VERSION 5.7 ;
BUSBITCHARS "[]" ;
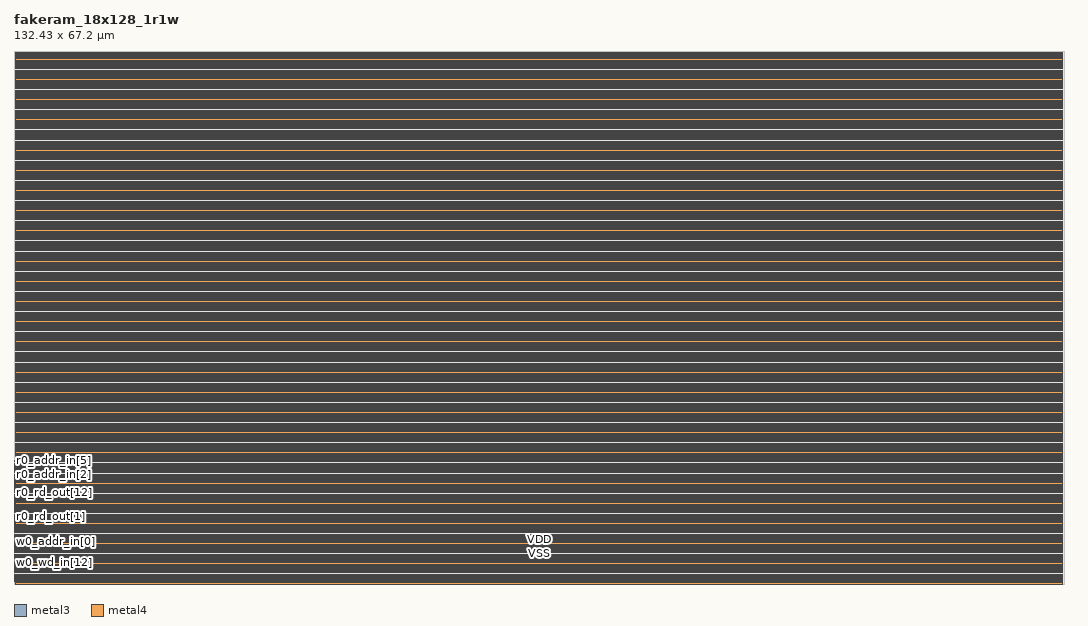
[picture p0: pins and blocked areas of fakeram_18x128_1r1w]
MACRO fakeram_18x128_1r1w
  FOREIGN fakeram_18x128_1r1w 0 0 ;
  SYMMETRY X Y R90 ;
  SIZE 132.430 BY 67.200 ;
  CLASS BLOCK ;
  PIN w0_wd_in[0]
    DIRECTION INPUT ;
    USE SIGNAL ;
    SHAPE ABUTMENT ;
    PORT
      LAYER metal3 ;
      RECT 0.000 0.280 0.140 0.420 ;
    END
  END w0_wd_in[0]
  PIN w0_wd_in[1]
    DIRECTION INPUT ;
    USE SIGNAL ;
    SHAPE ABUTMENT ;
    PORT
      LAYER metal3 ;
      RECT 0.000 0.560 0.140 0.700 ;
    END
  END w0_wd_in[1]
  PIN w0_wd_in[2]
    DIRECTION INPUT ;
    USE SIGNAL ;
    SHAPE ABUTMENT ;
    PORT
      LAYER metal3 ;
      RECT 0.000 0.840 0.140 0.980 ;
    END
  END w0_wd_in[2]
  PIN w0_wd_in[3]
    DIRECTION INPUT ;
    USE SIGNAL ;
    SHAPE ABUTMENT ;
    PORT
      LAYER metal3 ;
      RECT 0.000 1.120 0.140 1.260 ;
    END
  END w0_wd_in[3]
  PIN w0_wd_in[4]
    DIRECTION INPUT ;
    USE SIGNAL ;
    SHAPE ABUTMENT ;
    PORT
      LAYER metal3 ;
      RECT 0.000 1.400 0.140 1.540 ;
    END
  END w0_wd_in[4]
  PIN w0_wd_in[5]
    DIRECTION INPUT ;
    USE SIGNAL ;
    SHAPE ABUTMENT ;
    PORT
      LAYER metal3 ;
      RECT 0.000 1.680 0.140 1.820 ;
    END
  END w0_wd_in[5]
  PIN w0_wd_in[6]
    DIRECTION INPUT ;
    USE SIGNAL ;
    SHAPE ABUTMENT ;
    PORT
      LAYER metal3 ;
      RECT 0.000 1.960 0.140 2.100 ;
    END
  END w0_wd_in[6]
  PIN w0_wd_in[7]
    DIRECTION INPUT ;
    USE SIGNAL ;
    SHAPE ABUTMENT ;
    PORT
      LAYER metal3 ;
      RECT 0.000 2.240 0.140 2.380 ;
    END
  END w0_wd_in[7]
  PIN w0_wd_in[8]
    DIRECTION INPUT ;
    USE SIGNAL ;
    SHAPE ABUTMENT ;
    PORT
      LAYER metal3 ;
      RECT 0.000 2.520 0.140 2.660 ;
    END
  END w0_wd_in[8]
  PIN w0_wd_in[9]
    DIRECTION INPUT ;
    USE SIGNAL ;
    SHAPE ABUTMENT ;
    PORT
      LAYER metal3 ;
      RECT 0.000 2.800 0.140 2.940 ;
    END
  END w0_wd_in[9]
  PIN w0_wd_in[10]
    DIRECTION INPUT ;
    USE SIGNAL ;
    SHAPE ABUTMENT ;
    PORT
      LAYER metal3 ;
      RECT 0.000 3.080 0.140 3.220 ;
    END
  END w0_wd_in[10]
  PIN w0_wd_in[11]
    DIRECTION INPUT ;
    USE SIGNAL ;
    SHAPE ABUTMENT ;
    PORT
      LAYER metal3 ;
      RECT 0.000 3.360 0.140 3.500 ;
    END
  END w0_wd_in[11]
  PIN w0_wd_in[12]
    DIRECTION INPUT ;
    USE SIGNAL ;
    SHAPE ABUTMENT ;
    PORT
      LAYER metal3 ;
      RECT 0.000 3.640 0.140 3.780 ;
    END
  END w0_wd_in[12]
  PIN w0_wd_in[13]
    DIRECTION INPUT ;
    USE SIGNAL ;
    SHAPE ABUTMENT ;
    PORT
      LAYER metal3 ;
      RECT 0.000 3.920 0.140 4.060 ;
    END
  END w0_wd_in[13]
  PIN w0_wd_in[14]
    DIRECTION INPUT ;
    USE SIGNAL ;
    SHAPE ABUTMENT ;
    PORT
      LAYER metal3 ;
      RECT 0.000 4.200 0.140 4.340 ;
    END
  END w0_wd_in[14]
  PIN w0_wd_in[15]
    DIRECTION INPUT ;
    USE SIGNAL ;
    SHAPE ABUTMENT ;
    PORT
      LAYER metal3 ;
      RECT 0.000 4.480 0.140 4.620 ;
    END
  END w0_wd_in[15]
  PIN w0_wd_in[16]
    DIRECTION INPUT ;
    USE SIGNAL ;
    SHAPE ABUTMENT ;
    PORT
      LAYER metal3 ;
      RECT 0.000 4.760 0.140 4.900 ;
    END
  END w0_wd_in[16]
  PIN w0_wd_in[17]
    DIRECTION INPUT ;
    USE SIGNAL ;
    SHAPE ABUTMENT ;
    PORT
      LAYER metal3 ;
      RECT 0.000 5.040 0.140 5.180 ;
    END
  END w0_wd_in[17]
  PIN w0_addr_in[0]
    DIRECTION INPUT ;
    USE SIGNAL ;
    SHAPE ABUTMENT ;
    PORT
      LAYER metal3 ;
      RECT 0.000 5.320 0.140 5.460 ;
    END
  END w0_addr_in[0]
  PIN w0_addr_in[1]
    DIRECTION INPUT ;
    USE SIGNAL ;
    SHAPE ABUTMENT ;
    PORT
      LAYER metal3 ;
      RECT 0.000 5.600 0.140 5.740 ;
    END
  END w0_addr_in[1]
  PIN w0_addr_in[2]
    DIRECTION INPUT ;
    USE SIGNAL ;
    SHAPE ABUTMENT ;
    PORT
      LAYER metal3 ;
      RECT 0.000 5.880 0.140 6.020 ;
    END
  END w0_addr_in[2]
  PIN w0_addr_in[3]
    DIRECTION INPUT ;
    USE SIGNAL ;
    SHAPE ABUTMENT ;
    PORT
      LAYER metal3 ;
      RECT 0.000 6.160 0.140 6.300 ;
    END
  END w0_addr_in[3]
  PIN w0_addr_in[4]
    DIRECTION INPUT ;
    USE SIGNAL ;
    SHAPE ABUTMENT ;
    PORT
      LAYER metal3 ;
      RECT 0.000 6.440 0.140 6.580 ;
    END
  END w0_addr_in[4]
  PIN w0_addr_in[5]
    DIRECTION INPUT ;
    USE SIGNAL ;
    SHAPE ABUTMENT ;
    PORT
      LAYER metal3 ;
      RECT 0.000 6.720 0.140 6.860 ;
    END
  END w0_addr_in[5]
  PIN w0_addr_in[6]
    DIRECTION INPUT ;
    USE SIGNAL ;
    SHAPE ABUTMENT ;
    PORT
      LAYER metal3 ;
      RECT 0.000 7.000 0.140 7.140 ;
    END
  END w0_addr_in[6]
  PIN w0_clk
    DIRECTION INPUT ;
    USE SIGNAL ;
    SHAPE ABUTMENT ;
    PORT
      LAYER metal3 ;
      RECT 0.000 7.280 0.140 7.420 ;
    END
  END w0_clk
  PIN w0_ce_in
    DIRECTION INPUT ;
    USE SIGNAL ;
    SHAPE ABUTMENT ;
    PORT
      LAYER metal3 ;
      RECT 0.000 7.560 0.140 7.700 ;
    END
  END w0_ce_in
  PIN w0_we_in
    DIRECTION INPUT ;
    USE SIGNAL ;
    SHAPE ABUTMENT ;
    PORT
      LAYER metal3 ;
      RECT 0.000 7.840 0.140 7.980 ;
    END
  END w0_we_in
  PIN r0_rd_out[0]
    DIRECTION OUTPUT ;
    USE SIGNAL ;
    SHAPE ABUTMENT ;
    PORT
      LAYER metal3 ;
      RECT 0.000 8.120 0.140 8.260 ;
    END
  END r0_rd_out[0]
  PIN r0_rd_out[1]
    DIRECTION OUTPUT ;
    USE SIGNAL ;
    SHAPE ABUTMENT ;
    PORT
      LAYER metal3 ;
      RECT 0.000 8.400 0.140 8.540 ;
    END
  END r0_rd_out[1]
  PIN r0_rd_out[2]
    DIRECTION OUTPUT ;
    USE SIGNAL ;
    SHAPE ABUTMENT ;
    PORT
      LAYER metal3 ;
      RECT 0.000 8.680 0.140 8.820 ;
    END
  END r0_rd_out[2]
  PIN r0_rd_out[3]
    DIRECTION OUTPUT ;
    USE SIGNAL ;
    SHAPE ABUTMENT ;
    PORT
      LAYER metal3 ;
      RECT 0.000 8.960 0.140 9.100 ;
    END
  END r0_rd_out[3]
  PIN r0_rd_out[4]
    DIRECTION OUTPUT ;
    USE SIGNAL ;
    SHAPE ABUTMENT ;
    PORT
      LAYER metal3 ;
      RECT 0.000 9.240 0.140 9.380 ;
    END
  END r0_rd_out[4]
  PIN r0_rd_out[5]
    DIRECTION OUTPUT ;
    USE SIGNAL ;
    SHAPE ABUTMENT ;
    PORT
      LAYER metal3 ;
      RECT 0.000 9.520 0.140 9.660 ;
    END
  END r0_rd_out[5]
  PIN r0_rd_out[6]
    DIRECTION OUTPUT ;
    USE SIGNAL ;
    SHAPE ABUTMENT ;
    PORT
      LAYER metal3 ;
      RECT 0.000 9.800 0.140 9.940 ;
    END
  END r0_rd_out[6]
  PIN r0_rd_out[7]
    DIRECTION OUTPUT ;
    USE SIGNAL ;
    SHAPE ABUTMENT ;
    PORT
      LAYER metal3 ;
      RECT 0.000 10.080 0.140 10.220 ;
    END
  END r0_rd_out[7]
  PIN r0_rd_out[8]
    DIRECTION OUTPUT ;
    USE SIGNAL ;
    SHAPE ABUTMENT ;
    PORT
      LAYER metal3 ;
      RECT 0.000 10.360 0.140 10.500 ;
    END
  END r0_rd_out[8]
  PIN r0_rd_out[9]
    DIRECTION OUTPUT ;
    USE SIGNAL ;
    SHAPE ABUTMENT ;
    PORT
      LAYER metal3 ;
      RECT 0.000 10.640 0.140 10.780 ;
    END
  END r0_rd_out[9]
  PIN r0_rd_out[10]
    DIRECTION OUTPUT ;
    USE SIGNAL ;
    SHAPE ABUTMENT ;
    PORT
      LAYER metal3 ;
      RECT 0.000 10.920 0.140 11.060 ;
    END
  END r0_rd_out[10]
  PIN r0_rd_out[11]
    DIRECTION OUTPUT ;
    USE SIGNAL ;
    SHAPE ABUTMENT ;
    PORT
      LAYER metal3 ;
      RECT 0.000 11.200 0.140 11.340 ;
    END
  END r0_rd_out[11]
  PIN r0_rd_out[12]
    DIRECTION OUTPUT ;
    USE SIGNAL ;
    SHAPE ABUTMENT ;
    PORT
      LAYER metal3 ;
      RECT 0.000 11.480 0.140 11.620 ;
    END
  END r0_rd_out[12]
  PIN r0_rd_out[13]
    DIRECTION OUTPUT ;
    USE SIGNAL ;
    SHAPE ABUTMENT ;
    PORT
      LAYER metal3 ;
      RECT 0.000 11.760 0.140 11.900 ;
    END
  END r0_rd_out[13]
  PIN r0_rd_out[14]
    DIRECTION OUTPUT ;
    USE SIGNAL ;
    SHAPE ABUTMENT ;
    PORT
      LAYER metal3 ;
      RECT 0.000 12.040 0.140 12.180 ;
    END
  END r0_rd_out[14]
  PIN r0_rd_out[15]
    DIRECTION OUTPUT ;
    USE SIGNAL ;
    SHAPE ABUTMENT ;
    PORT
      LAYER metal3 ;
      RECT 0.000 12.320 0.140 12.460 ;
    END
  END r0_rd_out[15]
  PIN r0_rd_out[16]
    DIRECTION OUTPUT ;
    USE SIGNAL ;
    SHAPE ABUTMENT ;
    PORT
      LAYER metal3 ;
      RECT 0.000 12.600 0.140 12.740 ;
    END
  END r0_rd_out[16]
  PIN r0_rd_out[17]
    DIRECTION OUTPUT ;
    USE SIGNAL ;
    SHAPE ABUTMENT ;
    PORT
      LAYER metal3 ;
      RECT 0.000 12.880 0.140 13.020 ;
    END
  END r0_rd_out[17]
  PIN r0_addr_in[0]
    DIRECTION INPUT ;
    USE SIGNAL ;
    SHAPE ABUTMENT ;
    PORT
      LAYER metal3 ;
      RECT 0.000 13.160 0.140 13.300 ;
    END
  END r0_addr_in[0]
  PIN r0_addr_in[1]
    DIRECTION INPUT ;
    USE SIGNAL ;
    SHAPE ABUTMENT ;
    PORT
      LAYER metal3 ;
      RECT 0.000 13.440 0.140 13.580 ;
    END
  END r0_addr_in[1]
  PIN r0_addr_in[2]
    DIRECTION INPUT ;
    USE SIGNAL ;
    SHAPE ABUTMENT ;
    PORT
      LAYER metal3 ;
      RECT 0.000 13.720 0.140 13.860 ;
    END
  END r0_addr_in[2]
  PIN r0_addr_in[3]
    DIRECTION INPUT ;
    USE SIGNAL ;
    SHAPE ABUTMENT ;
    PORT
      LAYER metal3 ;
      RECT 0.000 14.000 0.140 14.140 ;
    END
  END r0_addr_in[3]
  PIN r0_addr_in[4]
    DIRECTION INPUT ;
    USE SIGNAL ;
    SHAPE ABUTMENT ;
    PORT
      LAYER metal3 ;
      RECT 0.000 14.280 0.140 14.420 ;
    END
  END r0_addr_in[4]
  PIN r0_addr_in[5]
    DIRECTION INPUT ;
    USE SIGNAL ;
    SHAPE ABUTMENT ;
    PORT
      LAYER metal3 ;
      RECT 0.000 14.560 0.140 14.700 ;
    END
  END r0_addr_in[5]
  PIN r0_addr_in[6]
    DIRECTION INPUT ;
    USE SIGNAL ;
    SHAPE ABUTMENT ;
    PORT
      LAYER metal3 ;
      RECT 0.000 14.840 0.140 14.980 ;
    END
  END r0_addr_in[6]
  PIN r0_clk
    DIRECTION INPUT ;
    USE SIGNAL ;
    SHAPE ABUTMENT ;
    PORT
      LAYER metal3 ;
      RECT 0.000 15.120 0.140 15.260 ;
    END
  END r0_clk
  PIN r0_ce_in
    DIRECTION INPUT ;
    USE SIGNAL ;
    SHAPE ABUTMENT ;
    PORT
      LAYER metal3 ;
      RECT 0.000 15.400 0.140 15.540 ;
    END
  END r0_ce_in
  PIN VDD
    DIRECTION INOUT ;
    USE POWER ;
    PORT
      LAYER metal4 ;
      RECT 0.190 0.000 132.240 0.140 ;
      RECT 0.190 0.560 132.240 0.700 ;
      RECT 0.190 1.120 132.240 1.260 ;
      RECT 0.190 1.680 132.240 1.820 ;
      RECT 0.190 2.240 132.240 2.380 ;
      RECT 0.190 2.800 132.240 2.940 ;
      RECT 0.190 3.360 132.240 3.500 ;
      RECT 0.190 3.920 132.240 4.060 ;
      RECT 0.190 4.480 132.240 4.620 ;
      RECT 0.190 5.040 132.240 5.180 ;
      RECT 0.190 5.600 132.240 5.740 ;
      RECT 0.190 6.160 132.240 6.300 ;
      RECT 0.190 6.720 132.240 6.860 ;
      RECT 0.190 7.280 132.240 7.420 ;
      RECT 0.190 7.840 132.240 7.980 ;
      RECT 0.190 8.400 132.240 8.540 ;
      RECT 0.190 8.960 132.240 9.100 ;
      RECT 0.190 9.520 132.240 9.660 ;
      RECT 0.190 10.080 132.240 10.220 ;
      RECT 0.190 10.640 132.240 10.780 ;
      RECT 0.190 11.200 132.240 11.340 ;
      RECT 0.190 11.760 132.240 11.900 ;
      RECT 0.190 12.320 132.240 12.460 ;
      RECT 0.190 12.880 132.240 13.020 ;
      RECT 0.190 13.440 132.240 13.580 ;
      RECT 0.190 14.000 132.240 14.140 ;
      RECT 0.190 14.560 132.240 14.700 ;
      RECT 0.190 15.120 132.240 15.260 ;
      RECT 0.190 15.680 132.240 15.820 ;
      RECT 0.190 16.240 132.240 16.380 ;
      RECT 0.190 16.800 132.240 16.940 ;
      RECT 0.190 17.360 132.240 17.500 ;
      RECT 0.190 17.920 132.240 18.060 ;
      RECT 0.190 18.480 132.240 18.620 ;
      RECT 0.190 19.040 132.240 19.180 ;
      RECT 0.190 19.600 132.240 19.740 ;
      RECT 0.190 20.160 132.240 20.300 ;
      RECT 0.190 20.720 132.240 20.860 ;
      RECT 0.190 21.280 132.240 21.420 ;
      RECT 0.190 21.840 132.240 21.980 ;
      RECT 0.190 22.400 132.240 22.540 ;
      RECT 0.190 22.960 132.240 23.100 ;
      RECT 0.190 23.520 132.240 23.660 ;
      RECT 0.190 24.080 132.240 24.220 ;
      RECT 0.190 24.640 132.240 24.780 ;
      RECT 0.190 25.200 132.240 25.340 ;
      RECT 0.190 25.760 132.240 25.900 ;
      RECT 0.190 26.320 132.240 26.460 ;
      RECT 0.190 26.880 132.240 27.020 ;
      RECT 0.190 27.440 132.240 27.580 ;
      RECT 0.190 28.000 132.240 28.140 ;
      RECT 0.190 28.560 132.240 28.700 ;
      RECT 0.190 29.120 132.240 29.260 ;
      RECT 0.190 29.680 132.240 29.820 ;
      RECT 0.190 30.240 132.240 30.380 ;
      RECT 0.190 30.800 132.240 30.940 ;
      RECT 0.190 31.360 132.240 31.500 ;
      RECT 0.190 31.920 132.240 32.060 ;
      RECT 0.190 32.480 132.240 32.620 ;
      RECT 0.190 33.040 132.240 33.180 ;
      RECT 0.190 33.600 132.240 33.740 ;
      RECT 0.190 34.160 132.240 34.300 ;
      RECT 0.190 34.720 132.240 34.860 ;
      RECT 0.190 35.280 132.240 35.420 ;
      RECT 0.190 35.840 132.240 35.980 ;
      RECT 0.190 36.400 132.240 36.540 ;
      RECT 0.190 36.960 132.240 37.100 ;
      RECT 0.190 37.520 132.240 37.660 ;
      RECT 0.190 38.080 132.240 38.220 ;
      RECT 0.190 38.640 132.240 38.780 ;
      RECT 0.190 39.200 132.240 39.340 ;
      RECT 0.190 39.760 132.240 39.900 ;
      RECT 0.190 40.320 132.240 40.460 ;
      RECT 0.190 40.880 132.240 41.020 ;
      RECT 0.190 41.440 132.240 41.580 ;
      RECT 0.190 42.000 132.240 42.140 ;
      RECT 0.190 42.560 132.240 42.700 ;
      RECT 0.190 43.120 132.240 43.260 ;
      RECT 0.190 43.680 132.240 43.820 ;
      RECT 0.190 44.240 132.240 44.380 ;
      RECT 0.190 44.800 132.240 44.940 ;
      RECT 0.190 45.360 132.240 45.500 ;
      RECT 0.190 45.920 132.240 46.060 ;
      RECT 0.190 46.480 132.240 46.620 ;
      RECT 0.190 47.040 132.240 47.180 ;
      RECT 0.190 47.600 132.240 47.740 ;
      RECT 0.190 48.160 132.240 48.300 ;
      RECT 0.190 48.720 132.240 48.860 ;
      RECT 0.190 49.280 132.240 49.420 ;
      RECT 0.190 49.840 132.240 49.980 ;
      RECT 0.190 50.400 132.240 50.540 ;
      RECT 0.190 50.960 132.240 51.100 ;
      RECT 0.190 51.520 132.240 51.660 ;
      RECT 0.190 52.080 132.240 52.220 ;
      RECT 0.190 52.640 132.240 52.780 ;
      RECT 0.190 53.200 132.240 53.340 ;
      RECT 0.190 53.760 132.240 53.900 ;
      RECT 0.190 54.320 132.240 54.460 ;
      RECT 0.190 54.880 132.240 55.020 ;
      RECT 0.190 55.440 132.240 55.580 ;
      RECT 0.190 56.000 132.240 56.140 ;
      RECT 0.190 56.560 132.240 56.700 ;
      RECT 0.190 57.120 132.240 57.260 ;
      RECT 0.190 57.680 132.240 57.820 ;
      RECT 0.190 58.240 132.240 58.380 ;
      RECT 0.190 58.800 132.240 58.940 ;
      RECT 0.190 59.360 132.240 59.500 ;
      RECT 0.190 59.920 132.240 60.060 ;
      RECT 0.190 60.480 132.240 60.620 ;
      RECT 0.190 61.040 132.240 61.180 ;
      RECT 0.190 61.600 132.240 61.740 ;
      RECT 0.190 62.160 132.240 62.300 ;
      RECT 0.190 62.720 132.240 62.860 ;
      RECT 0.190 63.280 132.240 63.420 ;
      RECT 0.190 63.840 132.240 63.980 ;
      RECT 0.190 64.400 132.240 64.540 ;
      RECT 0.190 64.960 132.240 65.100 ;
      RECT 0.190 65.520 132.240 65.660 ;
      RECT 0.190 66.080 132.240 66.220 ;
      RECT 0.190 66.640 132.240 66.780 ;
    END
  END VDD
  PIN VSS
    DIRECTION INOUT ;
    USE GROUND ;
    PORT
      LAYER metal4 ;
      RECT 0.190 0.280 132.240 0.420 ;
      RECT 0.190 0.840 132.240 0.980 ;
      RECT 0.190 1.400 132.240 1.540 ;
      RECT 0.190 1.960 132.240 2.100 ;
      RECT 0.190 2.520 132.240 2.660 ;
      RECT 0.190 3.080 132.240 3.220 ;
      RECT 0.190 3.640 132.240 3.780 ;
      RECT 0.190 4.200 132.240 4.340 ;
      RECT 0.190 4.760 132.240 4.900 ;
      RECT 0.190 5.320 132.240 5.460 ;
      RECT 0.190 5.880 132.240 6.020 ;
      RECT 0.190 6.440 132.240 6.580 ;
      RECT 0.190 7.000 132.240 7.140 ;
      RECT 0.190 7.560 132.240 7.700 ;
      RECT 0.190 8.120 132.240 8.260 ;
      RECT 0.190 8.680 132.240 8.820 ;
      RECT 0.190 9.240 132.240 9.380 ;
      RECT 0.190 9.800 132.240 9.940 ;
      RECT 0.190 10.360 132.240 10.500 ;
      RECT 0.190 10.920 132.240 11.060 ;
      RECT 0.190 11.480 132.240 11.620 ;
      RECT 0.190 12.040 132.240 12.180 ;
      RECT 0.190 12.600 132.240 12.740 ;
      RECT 0.190 13.160 132.240 13.300 ;
      RECT 0.190 13.720 132.240 13.860 ;
      RECT 0.190 14.280 132.240 14.420 ;
      RECT 0.190 14.840 132.240 14.980 ;
      RECT 0.190 15.400 132.240 15.540 ;
      RECT 0.190 15.960 132.240 16.100 ;
      RECT 0.190 16.520 132.240 16.660 ;
      RECT 0.190 17.080 132.240 17.220 ;
      RECT 0.190 17.640 132.240 17.780 ;
      RECT 0.190 18.200 132.240 18.340 ;
      RECT 0.190 18.760 132.240 18.900 ;
      RECT 0.190 19.320 132.240 19.460 ;
      RECT 0.190 19.880 132.240 20.020 ;
      RECT 0.190 20.440 132.240 20.580 ;
      RECT 0.190 21.000 132.240 21.140 ;
      RECT 0.190 21.560 132.240 21.700 ;
      RECT 0.190 22.120 132.240 22.260 ;
      RECT 0.190 22.680 132.240 22.820 ;
      RECT 0.190 23.240 132.240 23.380 ;
      RECT 0.190 23.800 132.240 23.940 ;
      RECT 0.190 24.360 132.240 24.500 ;
      RECT 0.190 24.920 132.240 25.060 ;
      RECT 0.190 25.480 132.240 25.620 ;
      RECT 0.190 26.040 132.240 26.180 ;
      RECT 0.190 26.600 132.240 26.740 ;
      RECT 0.190 27.160 132.240 27.300 ;
      RECT 0.190 27.720 132.240 27.860 ;
      RECT 0.190 28.280 132.240 28.420 ;
      RECT 0.190 28.840 132.240 28.980 ;
      RECT 0.190 29.400 132.240 29.540 ;
      RECT 0.190 29.960 132.240 30.100 ;
      RECT 0.190 30.520 132.240 30.660 ;
      RECT 0.190 31.080 132.240 31.220 ;
      RECT 0.190 31.640 132.240 31.780 ;
      RECT 0.190 32.200 132.240 32.340 ;
      RECT 0.190 32.760 132.240 32.900 ;
      RECT 0.190 33.320 132.240 33.460 ;
      RECT 0.190 33.880 132.240 34.020 ;
      RECT 0.190 34.440 132.240 34.580 ;
      RECT 0.190 35.000 132.240 35.140 ;
      RECT 0.190 35.560 132.240 35.700 ;
      RECT 0.190 36.120 132.240 36.260 ;
      RECT 0.190 36.680 132.240 36.820 ;
      RECT 0.190 37.240 132.240 37.380 ;
      RECT 0.190 37.800 132.240 37.940 ;
      RECT 0.190 38.360 132.240 38.500 ;
      RECT 0.190 38.920 132.240 39.060 ;
      RECT 0.190 39.480 132.240 39.620 ;
      RECT 0.190 40.040 132.240 40.180 ;
      RECT 0.190 40.600 132.240 40.740 ;
      RECT 0.190 41.160 132.240 41.300 ;
      RECT 0.190 41.720 132.240 41.860 ;
      RECT 0.190 42.280 132.240 42.420 ;
      RECT 0.190 42.840 132.240 42.980 ;
      RECT 0.190 43.400 132.240 43.540 ;
      RECT 0.190 43.960 132.240 44.100 ;
      RECT 0.190 44.520 132.240 44.660 ;
      RECT 0.190 45.080 132.240 45.220 ;
      RECT 0.190 45.640 132.240 45.780 ;
      RECT 0.190 46.200 132.240 46.340 ;
      RECT 0.190 46.760 132.240 46.900 ;
      RECT 0.190 47.320 132.240 47.460 ;
      RECT 0.190 47.880 132.240 48.020 ;
      RECT 0.190 48.440 132.240 48.580 ;
      RECT 0.190 49.000 132.240 49.140 ;
      RECT 0.190 49.560 132.240 49.700 ;
      RECT 0.190 50.120 132.240 50.260 ;
      RECT 0.190 50.680 132.240 50.820 ;
      RECT 0.190 51.240 132.240 51.380 ;
      RECT 0.190 51.800 132.240 51.940 ;
      RECT 0.190 52.360 132.240 52.500 ;
      RECT 0.190 52.920 132.240 53.060 ;
      RECT 0.190 53.480 132.240 53.620 ;
      RECT 0.190 54.040 132.240 54.180 ;
      RECT 0.190 54.600 132.240 54.740 ;
      RECT 0.190 55.160 132.240 55.300 ;
      RECT 0.190 55.720 132.240 55.860 ;
      RECT 0.190 56.280 132.240 56.420 ;
      RECT 0.190 56.840 132.240 56.980 ;
      RECT 0.190 57.400 132.240 57.540 ;
      RECT 0.190 57.960 132.240 58.100 ;
      RECT 0.190 58.520 132.240 58.660 ;
      RECT 0.190 59.080 132.240 59.220 ;
      RECT 0.190 59.640 132.240 59.780 ;
      RECT 0.190 60.200 132.240 60.340 ;
      RECT 0.190 60.760 132.240 60.900 ;
      RECT 0.190 61.320 132.240 61.460 ;
      RECT 0.190 61.880 132.240 62.020 ;
      RECT 0.190 62.440 132.240 62.580 ;
      RECT 0.190 63.000 132.240 63.140 ;
      RECT 0.190 63.560 132.240 63.700 ;
      RECT 0.190 64.120 132.240 64.260 ;
      RECT 0.190 64.680 132.240 64.820 ;
      RECT 0.190 65.240 132.240 65.380 ;
      RECT 0.190 65.800 132.240 65.940 ;
      RECT 0.190 66.360 132.240 66.500 ;
      RECT 0.190 66.920 132.240 67.060 ;
    END
  END VSS
  OBS
    LAYER metal1 ;
      RECT 0.000 0.000 132.430 67.200 ;
    LAYER metal2 ;
      RECT 0.000 0.000 132.430 67.200 ;
    LAYER metal3 ;
      RECT 0.000 0.000 132.430 67.200 ;
  END
END fakeram_18x128_1r1w
END LIBRARY
